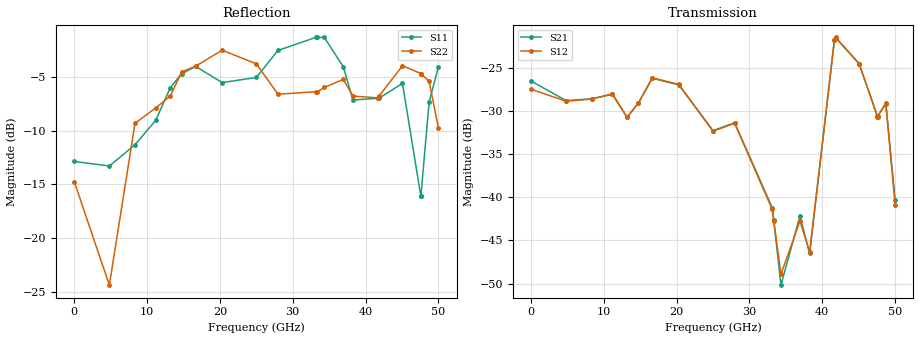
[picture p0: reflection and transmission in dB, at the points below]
!Keysight Technologies,N5245B,MY58422270,A.16.20.02
!Date: Thursday, March 05, 2026 01:36:27
!Correction: S11(C  2-Port  )
!S21(C  2-Port  )
!S12(C  2-Port  )
!S22(C  2-Port  )
!S2P File: Measurements: S11, S21, S12, S22:
# Hz S  dB  R 50
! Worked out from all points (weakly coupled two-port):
!   3201 points, 10 MHz to 50 GHz, reference 50 ohm
!   highest |S21| = -21.52 dB at 41.85 GHz (marker M1); lowest = -50.2 dB at 34.33 GHz (marker M2)
!   lowest |S11| = -16.1 dB at 47.58 GHz (marker M3), VSWR 1.37, Z = 45.4 + j14.4 ohm
!   |S11| at or under -10 dB: start of sweep to 9.789 GHz; 11.44 GHz to 11.87 GHz (421.3 MHz wide, 3.61 % of centre); 46.75 GHz to 48.32 GHz (1.572 GHz wide, 3.31 % of centre)
!   |S22| runs from -24.4 to -2.5 dB; largest |S21 - S12| = 0.0099
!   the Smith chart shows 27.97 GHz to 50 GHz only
!   S11 on the Smith chart (normalised r, x): 27.97 GHz: 0.20, +0.57; 33.13 GHz: 0.67, +2.66; 36.94 GHz: 1.53, -1.91; 47.59 GHz: 0.92, +0.30; 50 GHz: 0.54, -1.08
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1e7  -12.87 -3.8  -26.50 6.7  -27.46 3.7  -14.73 34.5
4.837159e9  -13.29 -122.1  -28.79 179.1  -28.86 179.2  -24.34 -123.6
8.352081e9  -11.32 170.2  -28.58 33.5  -28.61 33.2  -9.33 -154.5
1.119526e10  -9.05 101.6  -28.06 -68.8  -28.00 -68.7  -7.91 92.3
1.321048e10  -6.02 61.4  -30.72 -119.6  -30.72 -120.1  -6.78 -17.5
1.475705e10  -4.73 13.4  -29.09 -148.5  -29.07 -148.3  -4.57 -88.5
1.667854e10  -4.06 -44.5  -26.20 157.6  -26.14 157.7  -4.03 -141.7
2.031844e10  -5.55 -126.5  -26.97 40.1  -26.91 40.1  -2.55 153.9
2.5005e10  -5.08 171.2  -32.27 -67.2  -32.34 -66.6  -3.81 70.7
2.797316e10  -2.57 119.3  -31.36 -131.9  -31.41 -134.6  -6.63 16.9
3.312838e10  -1.37 39.2  -41.19 12.7  -41.39 13.7  -6.40 -125.7
3.334708e10  -1.36 35.5  -42.64 4.5  -42.77 0.7  -6.42 -130.6
3.433126e10  -1.36 18.6  -50.18 -96.9  -48.93 -77.4  -6.00 -152.2
3.694011e10  -4.09 -37.5  -42.16 99.0  -42.75 95.9  -5.26 156.5
3.826797e10  -7.17 -20.5  -46.51 96.1  -46.33 -93.9  -6.80 134.0
4.167354e10  -7.01 -56.7  -21.71 -61.1  -21.71 -61.2  -6.97 113.5
4.184538e10  -7.00 -56.7  -21.52 -77.6  -21.46 -77.6  -6.81 112.4
4.506349e10  -5.63 -105.1  -24.53 89.6  -24.49 89.5  -3.99 76.0
4.757861e10  -16.07 99.2  -30.60 -13.8  -30.68 -12.4  -4.71 41.6
4.759423e10  -16.04 96.5  -30.58 -13.9  -30.66 -12.7  -4.71 41.4
4.871901e10  -7.37 -26.2  -29.16 -90.4  -29.06 -89.9  -5.44 19.5
5e10  -4.08 -77.9  -40.26 -135.0  -40.91 -129.0  -9.77 7.4
